One B-rep face of a CAD part: STEP entity #177.
In plain terms, the planar face has unit normal (0, 0, -1).
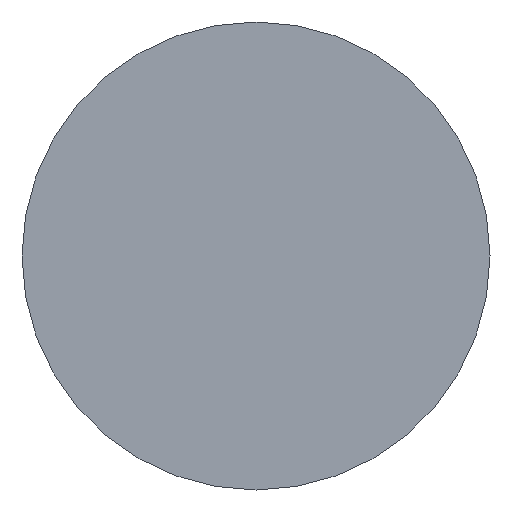
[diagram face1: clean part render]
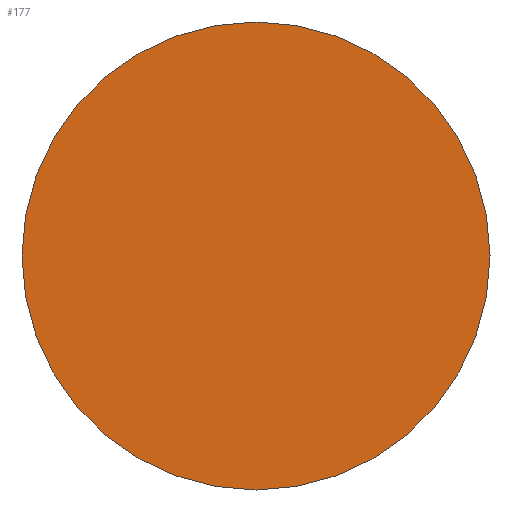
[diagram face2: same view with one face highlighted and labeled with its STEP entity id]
Its self-contained STEP definition (entity closure, numbers rounded to 3 decimals):
#49 = CONICAL_SURFACE('',#50,2.35,0.633);
#50 = AXIS2_PLACEMENT_3D('',#51,#52,#53);
#51 = CARTESIAN_POINT('',(0.,0.,0.));
#52 = DIRECTION('',(-0.,-0.,-1.));
#53 = DIRECTION('',(1.,0.,-0.));
#73 = VERTEX_POINT('',#74);
#74 = CARTESIAN_POINT('',(2.35,0.,0.));
#95 = EDGE_CURVE('',#73,#73,#96,.T.);
#96 = SURFACE_CURVE('',#97,(#102,#109),.PCURVE_S1.);
#97 = CIRCLE('',#98,2.35);
#98 = AXIS2_PLACEMENT_3D('',#99,#100,#101);
#99 = CARTESIAN_POINT('',(0.,0.,0.));
#100 = DIRECTION('',(0.,0.,1.));
#101 = DIRECTION('',(1.,0.,-0.));
#102 = PCURVE('',#49,#103);
#103 = DEFINITIONAL_REPRESENTATION('',(#104),#108);
#104 = LINE('',#105,#106);
#105 = CARTESIAN_POINT('',(-0.,-0.));
#106 = VECTOR('',#107,1.);
#107 = DIRECTION('',(-1.,-0.));
#108 = ( GEOMETRIC_REPRESENTATION_CONTEXT(2) 
PARAMETRIC_REPRESENTATION_CONTEXT() REPRESENTATION_CONTEXT('2D SPACE',''
  ) );
#109 = PCURVE('',#110,#115);
#110 = PLANE('',#111);
#111 = AXIS2_PLACEMENT_3D('',#112,#113,#114);
#112 = CARTESIAN_POINT('',(0.,0.,0.));
#113 = DIRECTION('',(0.,0.,1.));
#114 = DIRECTION('',(1.,0.,-0.));
#115 = DEFINITIONAL_REPRESENTATION('',(#116),#120);
#116 = CIRCLE('',#117,2.35);
#117 = AXIS2_PLACEMENT_2D('',#118,#119);
#118 = CARTESIAN_POINT('',(0.,0.));
#119 = DIRECTION('',(1.,0.));
#120 = ( GEOMETRIC_REPRESENTATION_CONTEXT(2) 
PARAMETRIC_REPRESENTATION_CONTEXT() REPRESENTATION_CONTEXT('2D SPACE',''
  ) );
#177 = ADVANCED_FACE('',(#178),#110,.F.);
#178 = FACE_BOUND('',#179,.T.);
#179 = EDGE_LOOP('',(#180));
#180 = ORIENTED_EDGE('',*,*,#95,.F.);
